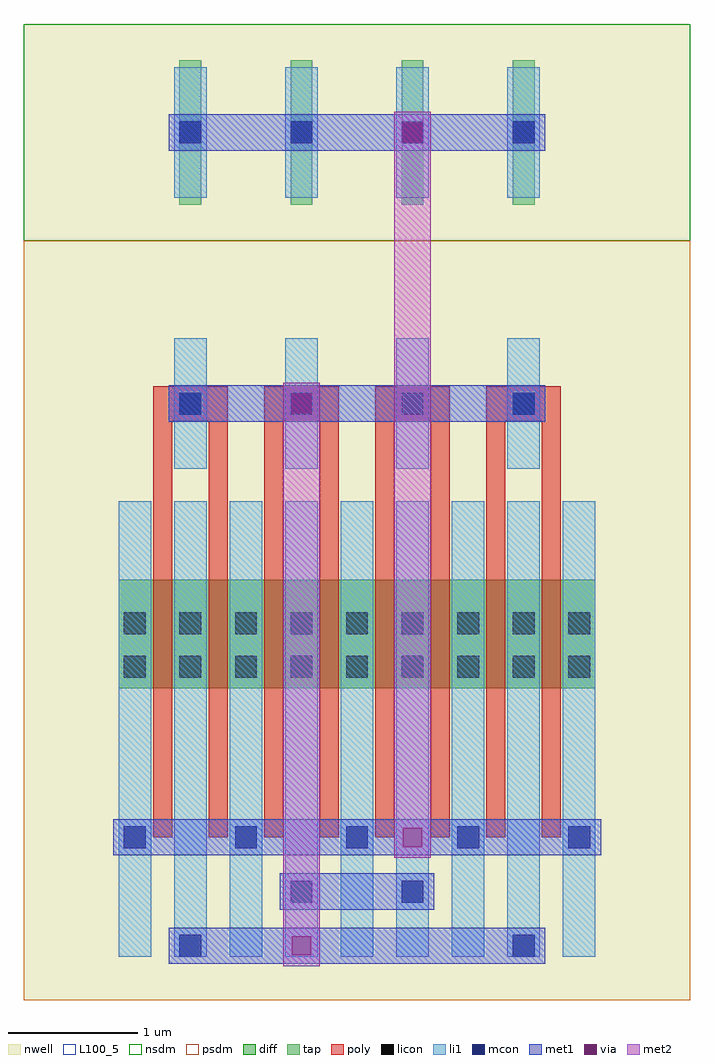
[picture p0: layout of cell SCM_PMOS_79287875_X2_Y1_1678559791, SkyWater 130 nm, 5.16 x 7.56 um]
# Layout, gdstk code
import gdstk
lib = gdstk.Library(unit=1e-6, precision=1e-09)
def R(c, l, rs):  # rectangles x0, y0, x1, y1
    for r in rs: c.add(gdstk.rectangle(r[:2], r[2:], *l))
def A(c, l, x, y, w, h, nx, ny, dx, dy):  # array of equal rectangles
    R(c, l, [(x+i*dx, y+j*dy, x+i*dx+w, y+j*dy+h) for i in range(nx) for j in range(ny)])
nwell = (64, 20)
diff = (65, 20)
tap = (65, 44)
poly = (66, 20)
licon = (66, 44)
li1 = (67, 20)
mcon = (67, 44)
met1 = (68, 20)
via = (68, 44)
met2 = (69, 20)
nsdm = (93, 44)
psdm = (94, 20)
L100_5 = (100, 5)

scm_pmos_79287875_x2_y1_ = lib.new_cell('SCM_PMOS_79287875_X2_Y1_1678559791')
R(scm_pmos_79287875_x2_y1_, nwell, [(0,0,5.16,7.56)])
R(scm_pmos_79287875_x2_y1_, diff, [(0.735,2.415,4.425,3.255)])
A(scm_pmos_79287875_x2_y1_, tap, 1.205, 6.16, 0.17, 1.12, 4, 1, 0.86, 0)
A(scm_pmos_79287875_x2_y1_, poly, 1, 1.26, 0.15, 3.36, 8, 1, 0.43, 0)
A(scm_pmos_79287875_x2_y1_, poly, 1, 4.485, 0.58, 0.27, 4, 1, 0.86, 0)
A(scm_pmos_79287875_x2_y1_, licon, 0.775, 2.495, 0.17, 0.17, 3, 2, 0.43, 0.34)
A(scm_pmos_79287875_x2_y1_, licon, 1.635, 2.495, 0.17, 0.17, 3, 2, 0.43, 0.34)
A(scm_pmos_79287875_x2_y1_, licon, 2.495, 2.495, 0.17, 0.17, 3, 2, 0.43, 0.34)
A(scm_pmos_79287875_x2_y1_, licon, 3.355, 2.495, 0.17, 0.17, 3, 2, 0.43, 0.34)
A(scm_pmos_79287875_x2_y1_, licon, 1.205, 4.535, 0.17, 0.17, 4, 2, 0.86, 2.1)
A(scm_pmos_79287875_x2_y1_, li1, 0.735, 0.335, 0.25, 3.53, 9, 1, 0.43, 0)
A(scm_pmos_79287875_x2_y1_, li1, 1.165, 4.115, 0.25, 1.01, 4, 2, 0.86, 2.1)
A(scm_pmos_79287875_x2_y1_, mcon, 0.775, 1.175, 0.17, 0.17, 5, 1, 0.86, 0)
A(scm_pmos_79287875_x2_y1_, mcon, 1.205, 4.535, 0.17, 0.17, 4, 2, 0.86, 2.1)
R(scm_pmos_79287875_x2_y1_, mcon, [(1.205,0.335,1.375,0.505), (3.785,0.335,3.955,0.505), (2.065,0.755,2.235,0.925), (2.925,0.755,3.095,0.925)])
R(scm_pmos_79287875_x2_y1_, met1, [(1.12,0.28,4.04,0.56), (1.98,0.7,3.18,0.98), (0.69,1.12,4.47,1.4), (1.12,4.48,4.04,4.76), (1.12,6.58,4.04,6.86)])
R(scm_pmos_79287875_x2_y1_, via, [(2.075,0.345,2.225,0.495), (2.935,1.185,3.085,1.335), (2.075,4.545,2.225,4.695), (2.935,6.645,3.085,6.795)])
R(scm_pmos_79287875_x2_y1_, met2, [(2.01,0.26,2.29,4.78), (2.87,1.1,3.15,6.88)])
R(scm_pmos_79287875_x2_y1_, nsdm, [(0,5.88,5.16,7.56)])
R(scm_pmos_79287875_x2_y1_, psdm, [(0,0,5.16,5.88)])
R(scm_pmos_79287875_x2_y1_, L100_5, [(0,0,5.16,7.56)])

lib.write_gds('SCM_PMOS_79287875_X2_Y1_1678559791.gds')
